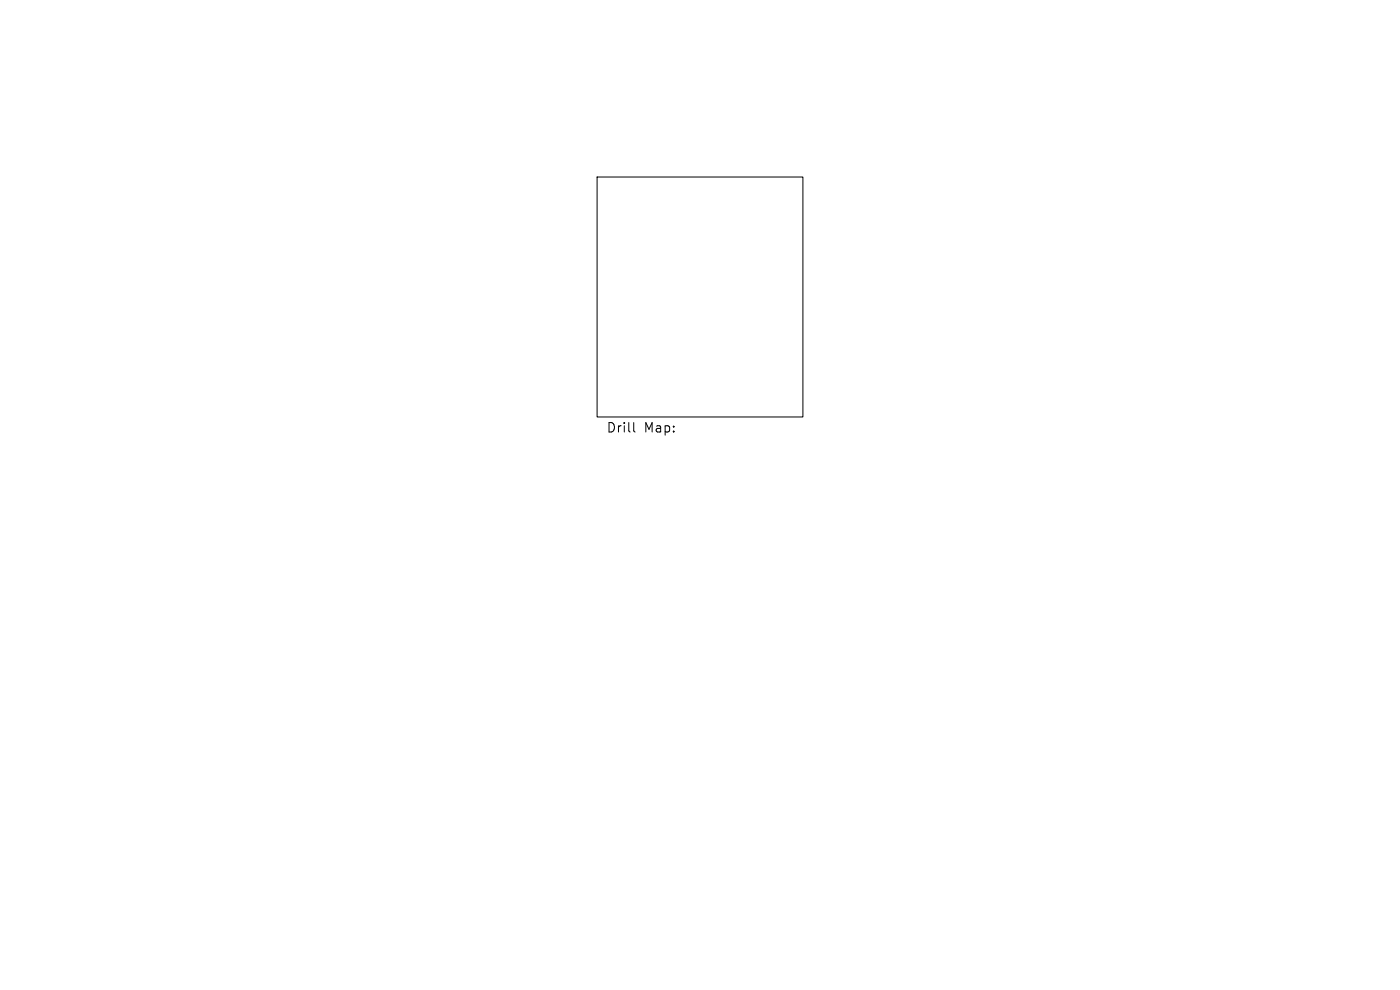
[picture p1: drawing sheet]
<svg xmlns="http://www.w3.org/2000/svg" width="297mm" height="210mm" viewBox="0 0 297 210" stroke-linecap="round" stroke-linejoin="round" font-family="sans-serif">
<defs><g id="words">
<g font-size="2.8">
<text x="128.6" y="92">Drill</text>
<text x="136.6" y="92">Map:</text>
</g>
</g></defs>
<path d="M126.7 37.6h43.6v50.9h-43.6zM134.4 89.6v1.8l.3 .2" fill="none" stroke="#000" stroke-width=".21"/>
<use href="#words"/>
</svg>
